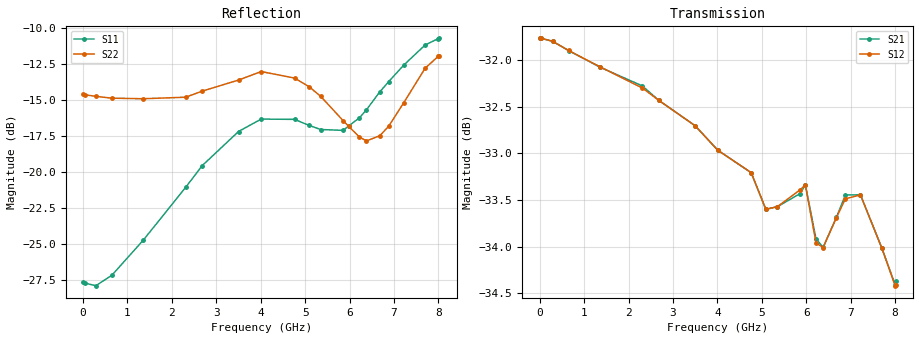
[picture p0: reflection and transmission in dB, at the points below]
! DEVICE ID: PE43712
! File Path: z:\PE43713\PE43713_CHAR_NOM_04292014\AMB\3p300\LS_ATT_30p50dB\PE43713_AMB_3p300V_3p000V_0p000V_LS_ATT_30p50dB_S2P_SN_10_A0139A.s2p
! Serial: 10
! Lot: A0139A
! Temp: 25C
! VDD: 3.300
! VSS: 0.000
! Control_Hi: 3.000
! Control_Lo: 0.000
! Attenuation Step: 30.50dB
! Port 1: RF1
! Port 2: RF2
! ThroughPath:1-2
! IDD: 0.000145674
! ISS: -1.021e-007
#  Hz  S  RI  R  50
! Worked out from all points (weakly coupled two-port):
!   801 points, 10 MHz to 8.01 GHz, reference 50 ohm
!   highest |S21| = -31.76 dB at 40 MHz (marker M1); lowest = -34.4 dB at 8 GHz (marker M2)
!   lowest |S11| = -27.9 dB at 290 MHz (marker M3), VSWR 1.08, Z = 46.3 + j1.23 ohm
!   |S11| at or under -10 dB: start of sweep to end of sweep
!   |S22| runs from -17.9 to -11.9 dB; largest |S21 - S12| = 0.00012
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1e7  -0.0416 0.00091  0.0258 -0.000104  0.0258 -0.000109  -0.1867 0.00126
4e7  -0.0411 0.00282  0.0258 -0.000372  0.0258 -0.000358  -0.1859 0.00389
2.9e8  -0.0381 0.0133  0.0256 -0.00238  0.0256 -0.00238  -0.1825 0.019
6.5e8  -0.0337 0.0281  0.0249 -0.0051  0.0249 -0.00511  -0.1763 0.0404
1.35e9  -0.021 0.054  0.0229 -0.00979  0.0229 -0.00982  -0.1618 0.079
2.31e9  0.0103 0.088  0.019 -0.0152  0.019 -0.0151  -0.1268 0.1309
2.68e9  0.0251 0.1023  0.0171 -0.0167  0.0171 -0.0167  -0.1107 0.156
3.5e9  0.0484 0.1298  0.0125 -0.0195  0.0125 -0.0195  -0.0863 0.1904
4.01e9  0.0582 0.1415  0.00943 -0.0204  0.00942 -0.0204  -0.0823 0.2081
4.76e9  0.0722 0.1345  0.00532 -0.0212  0.00534 -0.0212  -0.0667 0.2017
5.09e9  0.082 0.1201  0.00347 -0.0206  0.00349 -0.0206  -0.0582 0.1894
5.35e9  0.0911 0.1073  0.00258 -0.0208  0.00259 -0.0208  -0.0502 0.1765
5.86e9  0.1172 0.0762  -3.88e-05 -0.0213  -3.12e-05 -0.0214  -0.0133 0.1502
5.98e9  0.1263 0.0709  -0.00114 -0.0215  -0.00108 -0.0215  -0.00226 0.1443
6.22e9  0.1433 0.0576  -0.0024 -0.02  -0.00238 -0.0199  0.0241 0.1304
6.38e9  0.156 0.0533  -0.00232 -0.0198  -0.00227 -0.0198  0.0418 0.1215
6.68e9  0.1852 0.0435  -0.00345 -0.0204  -0.0034 -0.0204  0.0791 0.1081
6.88e9  0.2028 0.0386  -0.00487 -0.0207  -0.00486 -0.0206  0.1004 0.1039
7.22e9  0.233 0.0354  -0.00751 -0.0199  -0.0075 -0.0199  0.1394 0.105
7.7e9  0.274 0.0391  -0.00933 -0.0176  -0.00932 -0.0176  0.1971 0.118
8e9  0.2882 0.0427  -0.01 -0.0162  -0.00995 -0.0162  0.2203 0.125
8.01e9  0.2886 0.0433  -0.01 -0.0163  -0.00996 -0.0162  0.2211 0.1251
